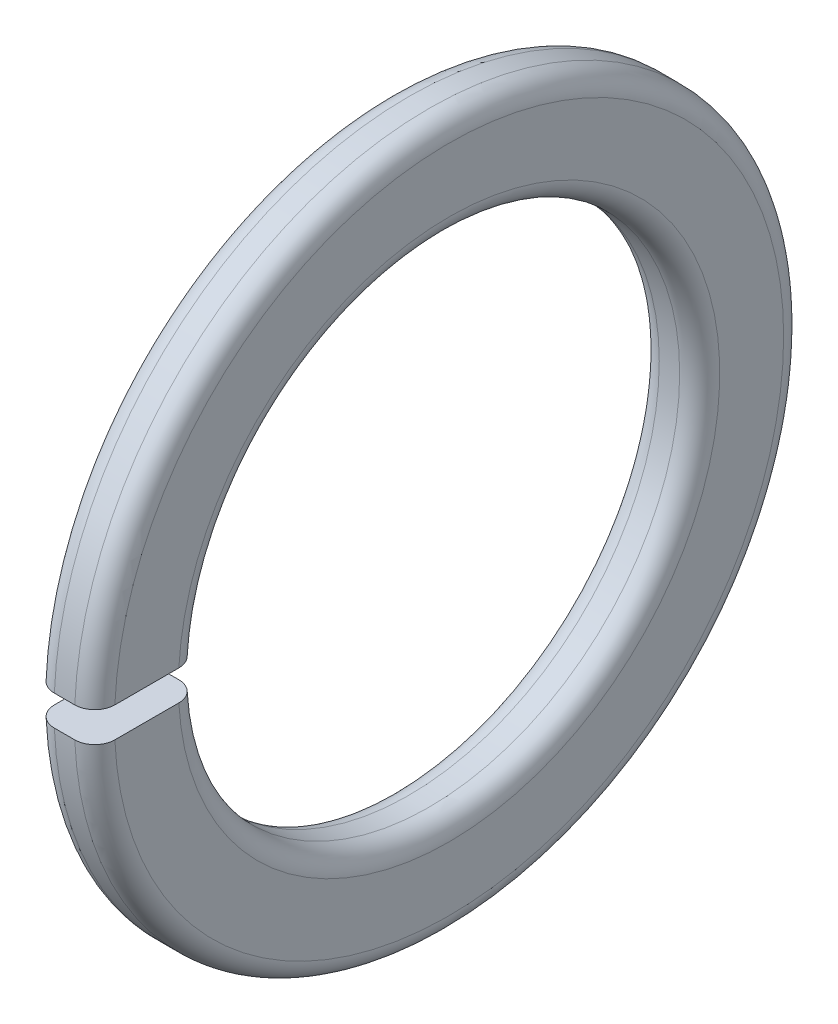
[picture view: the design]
ISO-10303-21;
HEADER;
FILE_DESCRIPTION(('STEP AP214'),'2;1');
FILE_NAME('part.step','',(''),(''),'','','');
FILE_SCHEMA(('AUTOMOTIVE_DESIGN { 1 0 10303 214 1 1 1 1 }'));
ENDSEC;
DATA;
#1=APPLICATION_CONTEXT('core data for automotive mechanical design processes');
#2=APPLICATION_PROTOCOL_DEFINITION('international standard','automotive_design',2000,#1);
#3=PRODUCT_CONTEXT('',#1,'mechanical');
#4=PRODUCT('Part','Part','',(#3));
#5=PRODUCT_RELATED_PRODUCT_CATEGORY('part','',(#4));
#6=PRODUCT_DEFINITION_FORMATION('','',#4);
#7=PRODUCT_DEFINITION_CONTEXT('part definition',#1,'design');
#8=PRODUCT_DEFINITION('design','',#6,#7);
#9=PRODUCT_DEFINITION_SHAPE('','',#8);
#10=(LENGTH_UNIT() NAMED_UNIT(*) SI_UNIT(.MILLI.,.METRE.));
#11=(NAMED_UNIT(*) PLANE_ANGLE_UNIT() SI_UNIT($,.RADIAN.));
#12=(NAMED_UNIT(*) SI_UNIT($,.STERADIAN.) SOLID_ANGLE_UNIT());
#13=UNCERTAINTY_MEASURE_WITH_UNIT(LENGTH_MEASURE(1.E-05),#10,'distance_accuracy_value','');
#14=(GEOMETRIC_REPRESENTATION_CONTEXT(3) GLOBAL_UNCERTAINTY_ASSIGNED_CONTEXT((#13)) GLOBAL_UNIT_ASSIGNED_CONTEXT((#10,
#11,#12)) REPRESENTATION_CONTEXT('',''));
#15=CARTESIAN_POINT('',(0.,0.,0.));
#16=DIRECTION('',(0.,0.,1.));
#17=DIRECTION('',(1.,0.,0.));
#18=AXIS2_PLACEMENT_3D('',#15,#16,#17);
#19=CARTESIAN_POINT('',(-5.35,0.,0.));
#20=DIRECTION('',(-1.,0.,0.));
#21=DIRECTION('',(0.,0.,1.));
#22=AXIS2_PLACEMENT_3D('',#19,#20,#21);
#23=TOROIDAL_SURFACE('',#22,35.8,2.65);
#24=CARTESIAN_POINT('',(-5.35,0.,0.));
#25=DIRECTION('',(-1.,0.,0.));
#26=DIRECTION('',(0.,0.,1.));
#27=AXIS2_PLACEMENT_3D('',#24,#25,#26);
#28=CIRCLE('',#27,33.15);
#29=CARTESIAN_POINT('',(-5.35,2.,33.0896131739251));
#30=VERTEX_POINT('',#29);
#31=CARTESIAN_POINT('',(-5.35,-2.,33.0896131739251));
#32=VERTEX_POINT('',#31);
#33=EDGE_CURVE('E129',#30,#32,#28,.T.);
#34=ORIENTED_EDGE('',*,*,#33,.F.);
#35=CARTESIAN_POINT('',(-6.71722156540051,2.,33.4702314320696));
#36=CARTESIAN_POINT('',(-6.84479830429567,2.,33.5472135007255));
#37=CARTESIAN_POINT('',(-6.96595921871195,2.,33.6350404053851));
#38=CARTESIAN_POINT('',(-7.19190739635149,2.,33.829873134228));
#39=CARTESIAN_POINT('',(-7.29667443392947,2.,33.9369023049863));
#40=CARTESIAN_POINT('',(-7.48670911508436,2.,34.1669771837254));
#41=CARTESIAN_POINT('',(-7.5719874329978,2.,34.2900140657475));
#42=CARTESIAN_POINT('',(-7.72068105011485,2.,34.5486108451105));
#43=CARTESIAN_POINT('',(-7.78410177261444,2.,34.6841676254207));
#44=CARTESIAN_POINT('',(-7.88739900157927,2.,34.9641700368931));
#45=CARTESIAN_POINT('',(-7.92724549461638,2.,35.1086267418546));
#46=CARTESIAN_POINT('',(-7.98214679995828,2.,35.4021828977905));
#47=CARTESIAN_POINT('',(-7.99720047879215,2.,35.5512825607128));
#48=CARTESIAN_POINT('',(-8.00208976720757,2.,35.8500277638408));
#49=CARTESIAN_POINT('',(-7.99190300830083,2.,35.9996736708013));
#50=CARTESIAN_POINT('',(-7.94654776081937,2.,36.2951307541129));
#51=CARTESIAN_POINT('',(-7.91137930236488,2.,36.4409419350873));
#52=CARTESIAN_POINT('',(-7.81705482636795,2.,36.7245672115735));
#53=CARTESIAN_POINT('',(-7.75790190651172,2.,36.8623823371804));
#54=CARTESIAN_POINT('',(-7.61727610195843,2.,37.126111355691));
#55=CARTESIAN_POINT('',(-7.53580335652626,2.,37.2520253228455));
#56=CARTESIAN_POINT('',(-7.35293406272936,2.,37.4882401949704));
#57=CARTESIAN_POINT('',(-7.25155754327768,2.,37.5985566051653));
#58=CARTESIAN_POINT('',(-7.03169977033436,2.,37.8005749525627));
#59=CARTESIAN_POINT('',(-6.91321862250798,2.,37.8922770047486));
#60=CARTESIAN_POINT('',(-6.66269124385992,2.,38.0543283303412));
#61=CARTESIAN_POINT('',(-6.53066406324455,2.,38.1247070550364));
#62=CARTESIAN_POINT('',(-6.25665775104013,2.,38.2422690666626));
#63=CARTESIAN_POINT('',(-6.11467869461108,2.,38.2894525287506));
#64=CARTESIAN_POINT('',(-5.82498400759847,2.,38.3592293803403));
#65=CARTESIAN_POINT('',(-5.67727553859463,2.,38.3818525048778));
#66=CARTESIAN_POINT('',(-5.38015750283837,2.,38.4019630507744));
#67=CARTESIAN_POINT('',(-5.23074794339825,2.,38.3994505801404));
#68=CARTESIAN_POINT('',(-4.9345633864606,2.,38.3693711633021));
#69=CARTESIAN_POINT('',(-4.78778686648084,2.,38.3418192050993));
#70=CARTESIAN_POINT('',(-4.50094127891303,2.,38.2624697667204));
#71=CARTESIAN_POINT('',(-4.36087220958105,2.,38.2106722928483));
#72=CARTESIAN_POINT('',(-4.09138125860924,2.,38.0842971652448));
#73=CARTESIAN_POINT('',(-3.96196171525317,2.,38.0097145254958));
#74=CARTESIAN_POINT('',(-3.71746522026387,2.,37.8398998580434));
#75=CARTESIAN_POINT('',(-3.6023883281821,2.,37.7446677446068));
#76=CARTESIAN_POINT('',(-3.3897221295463,2.,37.5361629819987));
#77=CARTESIAN_POINT('',(-3.29214974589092,2.,37.4228730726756));
#78=CARTESIAN_POINT('',(-3.1173786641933,2.,37.1815393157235));
#79=CARTESIAN_POINT('',(-3.04018010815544,2.,37.0534953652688));
#80=CARTESIAN_POINT('',(-2.90823555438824,2.,36.7861009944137));
#81=CARTESIAN_POINT('',(-2.85352042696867,2.,36.6467353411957));
#82=CARTESIAN_POINT('',(-2.76823109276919,2.,36.360803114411));
#83=CARTESIAN_POINT('',(-2.73765707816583,2.,36.2142364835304));
#84=CARTESIAN_POINT('',(-2.70148291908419,2.,35.9178656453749));
#85=CARTESIAN_POINT('',(-2.69591421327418,2.,35.7680576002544));
#86=CARTESIAN_POINT('',(-2.70999002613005,2.,35.4696305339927));
#87=CARTESIAN_POINT('',(-2.72963464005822,2.,35.321011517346));
#88=CARTESIAN_POINT('',(-2.79360178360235,2.,35.0290891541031));
#89=CARTESIAN_POINT('',(-2.83793900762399,2.,34.8857890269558));
#90=CARTESIAN_POINT('',(-2.95005178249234,2.,34.608670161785));
#91=CARTESIAN_POINT('',(-3.01782736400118,2.,34.4748514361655));
#92=CARTESIAN_POINT('',(-3.17487121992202,2.,34.2205596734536));
#93=CARTESIAN_POINT('',(-3.26413052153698,2.,34.1000810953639));
#94=CARTESIAN_POINT('',(-3.46163418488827,2.,33.8758444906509));
#95=CARTESIAN_POINT('',(-3.56987846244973,2.,33.7720863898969));
#96=CARTESIAN_POINT('',(-3.80212822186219,2.,33.5843882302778));
#97=CARTESIAN_POINT('',(-3.9261125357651,2.,33.500421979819));
#98=CARTESIAN_POINT('',(-4.18643262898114,2.,33.3545415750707));
#99=CARTESIAN_POINT('',(-4.32276780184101,2.,33.2926263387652));
#100=CARTESIAN_POINT('',(-4.60365809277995,2.,33.1927146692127));
#101=CARTESIAN_POINT('',(-4.74819788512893,2.,33.1546751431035));
#102=CARTESIAN_POINT('',(-5.04165499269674,2.,33.1034274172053));
#103=CARTESIAN_POINT('',(-5.19057335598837,2.,33.0902252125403));
#104=CARTESIAN_POINT('',(-5.4883866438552,2.,33.0890429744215));
#105=CARTESIAN_POINT('',(-5.63728150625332,2.,33.101044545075));
#106=CARTESIAN_POINT('',(-5.93081204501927,2.,33.1498886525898));
#107=CARTESIAN_POINT('',(-6.07545265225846,2.,33.1867011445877));
#108=CARTESIAN_POINT('',(-6.30326333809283,2.,33.2655921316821));
#109=CARTESIAN_POINT('',(-6.38901271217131,2.,33.300427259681));
#110=CARTESIAN_POINT('',(-6.55640555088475,2.,33.3788598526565));
#111=CARTESIAN_POINT('',(-6.63804901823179,2.,33.4224573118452));
#112=CARTESIAN_POINT('',(-6.71722156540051,2.,33.4702314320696));
#113=B_SPLINE_CURVE_WITH_KNOTS('',3,(#35,#36,#37,#38,#39,#40,#41,#42,#43,#44,#45,#46,#47,#48,
#49,#50,#51,#52,#53,#54,#55,#56,#57,#58,#59,#60,#61,#62,#63,#64,#65,#66,#67,#68,#69,#70,#71,#72,
#73,#74,#75,#76,#77,#78,#79,#80,#81,#82,#83,#84,#85,#86,#87,#88,#89,#90,#91,#92,#93,#94,#95,#96,
#97,#98,#99,#100,#101,#102,#103,#104,#105,#106,#107,#108,#109,#110,#111,#112),.UNSPECIFIED.,.T.,
.F.,(4,2,2,2,2,2,2,2,2,2,2,2,2,2,2,2,2,2,2,2,2,2,2,2,2,2,2,2,2,2,2,2,2,2,2,2,2,2,4),(0.,
0.446672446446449,0.893891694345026,1.34086540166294,1.78772812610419,2.23515855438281,
2.68260943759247,3.13045700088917,3.57830402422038,4.02609322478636,4.47387963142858,
4.92121772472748,5.36855305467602,5.81526768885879,6.26197894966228,6.70814877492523,
7.15431668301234,7.60021770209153,8.04611860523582,8.49211715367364,8.93811755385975,
9.384546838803,9.83097923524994,10.2780225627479,10.7250694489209,11.1726782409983,
11.6202887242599,12.0681658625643,12.5160435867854,12.963734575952,13.4114235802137,
13.8585167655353,14.305588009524,14.7518500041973,15.1982197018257,15.6442637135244,
16.0897685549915,16.3669681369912,16.6441675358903),.UNSPECIFIED.);
#114=CARTESIAN_POINT('',(-8.,2.,35.7440904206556));
#115=VERTEX_POINT('',#114);
#116=EDGE_CURVE('E53',#30,#115,#113,.T.);
#117=ORIENTED_EDGE('',*,*,#116,.T.);
#118=CARTESIAN_POINT('',(-8.,0.,0.));
#119=DIRECTION('',(-1.,0.,0.));
#120=DIRECTION('',(0.,0.,1.));
#121=AXIS2_PLACEMENT_3D('',#118,#119,#120);
#122=CIRCLE('',#121,35.8);
#123=CARTESIAN_POINT('',(-8.,-2.,35.7440904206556));
#124=VERTEX_POINT('',#123);
#125=EDGE_CURVE('E141',#115,#124,#122,.T.);
#126=ORIENTED_EDGE('',*,*,#125,.T.);
#127=CARTESIAN_POINT('',(-6.71722156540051,-2.,33.4702314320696));
#128=CARTESIAN_POINT('',(-6.58992742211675,-2.,33.3934353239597));
#129=CARTESIAN_POINT('',(-6.45606218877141,-2.,33.3273234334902));
#130=CARTESIAN_POINT('',(-6.17902217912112,-2.,33.2184562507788));
#131=CARTESIAN_POINT('',(-6.03583656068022,-2.,33.1757287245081));
#132=CARTESIAN_POINT('',(-5.74437135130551,-2.,33.1149479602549));
#133=CARTESIAN_POINT('',(-5.59609400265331,-2.,33.0968840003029));
#134=CARTESIAN_POINT('',(-5.29865213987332,-2.,33.0859280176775));
#135=CARTESIAN_POINT('',(-5.14948785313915,-2.,33.0930297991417));
#136=CARTESIAN_POINT('',(-4.85453503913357,-2.,33.1321755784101));
#137=CARTESIAN_POINT('',(-4.70874506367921,-2.,33.164208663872));
#138=CARTESIAN_POINT('',(-4.42460331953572,-2.,33.2522870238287));
#139=CARTESIAN_POINT('',(-4.28625184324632,-2.,33.3083332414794));
#140=CARTESIAN_POINT('',(-4.02085091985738,-2.,33.4428624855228));
#141=CARTESIAN_POINT('',(-3.89380636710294,-2.,33.5213551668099));
#142=CARTESIAN_POINT('',(-3.65467368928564,-2.,33.6985262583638));
#143=CARTESIAN_POINT('',(-3.54258563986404,-2.,33.7972047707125));
#144=CARTESIAN_POINT('',(-3.33637138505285,-2.,34.0120965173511));
#145=CARTESIAN_POINT('',(-3.24227141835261,-2.,34.1283349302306));
#146=CARTESIAN_POINT('',(-3.07488285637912,-2.,34.374937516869));
#147=CARTESIAN_POINT('',(-3.00159441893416,-2.,34.5053017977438));
#148=CARTESIAN_POINT('',(-2.87778215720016,-2.,34.7766916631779));
#149=CARTESIAN_POINT('',(-2.8272968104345,-2.,34.9177348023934));
#150=CARTESIAN_POINT('',(-2.75069197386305,-2.,35.2062900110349));
#151=CARTESIAN_POINT('',(-2.7245726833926,-2.,35.3538021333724));
#152=CARTESIAN_POINT('',(-2.69742089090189,-2.,35.6512829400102));
#153=CARTESIAN_POINT('',(-2.69641622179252,-2.,35.8012541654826));
#154=CARTESIAN_POINT('',(-2.71959596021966,-2.,36.0992375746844));
#155=CARTESIAN_POINT('',(-2.7437804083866,-2.,36.2472497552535));
#156=CARTESIAN_POINT('',(-2.81666433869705,-2.,36.5371264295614));
#157=CARTESIAN_POINT('',(-2.86536626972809,-2.,36.6789903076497));
#158=CARTESIAN_POINT('',(-2.98591548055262,-2.,36.9525180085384));
#159=CARTESIAN_POINT('',(-3.05776268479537,-2.,37.0841818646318));
#160=CARTESIAN_POINT('',(-3.22250313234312,-2.,37.3334497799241));
#161=CARTESIAN_POINT('',(-3.31537857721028,-2.,37.4510656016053));
#162=CARTESIAN_POINT('',(-3.51958167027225,-2.,37.6690088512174));
#163=CARTESIAN_POINT('',(-3.63090919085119,-2.,37.7693363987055));
#164=CARTESIAN_POINT('',(-3.86869555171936,-2.,37.9497101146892));
#165=CARTESIAN_POINT('',(-3.99513374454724,-2.,38.0297835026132));
#166=CARTESIAN_POINT('',(-4.25967225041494,-2.,38.1675344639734));
#167=CARTESIAN_POINT('',(-4.39777247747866,-2.,38.2252122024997));
#168=CARTESIAN_POINT('',(-4.68152226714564,-2.,38.3164595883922));
#169=CARTESIAN_POINT('',(-4.8271618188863,-2.,38.3500603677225));
#170=CARTESIAN_POINT('',(-5.12201587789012,-2.,38.3923134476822));
#171=CARTESIAN_POINT('',(-5.27123036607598,-2.,38.4009658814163));
#172=CARTESIAN_POINT('',(-5.56887772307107,-2.,38.3930777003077));
#173=CARTESIAN_POINT('',(-5.71731110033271,-2.,38.3765562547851));
#174=CARTESIAN_POINT('',(-6.00929711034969,-2.,38.3188284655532));
#175=CARTESIAN_POINT('',(-6.15284974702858,-2.,38.2776221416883));
#176=CARTESIAN_POINT('',(-6.43100776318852,-2.,38.1717004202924));
#177=CARTESIAN_POINT('',(-6.56561282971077,-2.,38.106984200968));
#178=CARTESIAN_POINT('',(-6.82205928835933,-2.,37.9558897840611));
#179=CARTESIAN_POINT('',(-6.94390065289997,-2.,37.8695115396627));
#180=CARTESIAN_POINT('',(-7.17147138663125,-2.,37.6774738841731));
#181=CARTESIAN_POINT('',(-7.27718750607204,-2.,37.5717987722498));
#182=CARTESIAN_POINT('',(-7.46940639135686,-2.,37.3442205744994));
#183=CARTESIAN_POINT('',(-7.5559089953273,-2.,37.2223173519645));
#184=CARTESIAN_POINT('',(-7.70736756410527,-2.,36.9655725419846));
#185=CARTESIAN_POINT('',(-7.77229500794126,-2.,36.8307141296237));
#186=CARTESIAN_POINT('',(-7.87862198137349,-2.,36.5520207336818));
#187=CARTESIAN_POINT('',(-7.92002128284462,-2.,36.4081856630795));
#188=CARTESIAN_POINT('',(-7.97817124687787,-2.,36.1154143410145));
#189=CARTESIAN_POINT('',(-7.99488857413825,-2.,35.9664714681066));
#190=CARTESIAN_POINT('',(-8.00310119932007,-2.,35.6678973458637));
#191=CARTESIAN_POINT('',(-7.99459733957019,-2.,35.5182661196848));
#192=CARTESIAN_POINT('',(-7.95259793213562,-2.,35.2224497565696));
#193=CARTESIAN_POINT('',(-7.91908542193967,-2.,35.0762670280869));
#194=CARTESIAN_POINT('',(-7.8279783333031,-2.,34.7915647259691));
#195=CARTESIAN_POINT('',(-7.77037776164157,-2.,34.6530470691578));
#196=CARTESIAN_POINT('',(-7.63271363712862,-2.,34.3876273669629));
#197=CARTESIAN_POINT('',(-7.55264340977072,-2.,34.2607287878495));
#198=CARTESIAN_POINT('',(-7.37236153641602,-2.,34.0223163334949));
#199=CARTESIAN_POINT('',(-7.27217432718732,-2.,33.9107840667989));
#200=CARTESIAN_POINT('',(-7.09527305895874,-2.,33.7444674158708));
#201=CARTESIAN_POINT('',(-7.02376787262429,-2.,33.6840465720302));
#202=CARTESIAN_POINT('',(-6.87478251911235,-2.,33.5710848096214));
#203=CARTESIAN_POINT('',(-6.79730235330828,-2.,33.5185438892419));
#204=CARTESIAN_POINT('',(-6.71722156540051,-2.,33.4702314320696));
#205=B_SPLINE_CURVE_WITH_KNOTS('',3,(#127,#128,#129,#130,#131,#132,#133,#134,#135,#136,#137,
#138,#139,#140,#141,#142,#143,#144,#145,#146,#147,#148,#149,#150,#151,#152,#153,#154,#155,#156,
#157,#158,#159,#160,#161,#162,#163,#164,#165,#166,#167,#168,#169,#170,#171,#172,#173,#174,#175,
#176,#177,#178,#179,#180,#181,#182,#183,#184,#185,#186,#187,#188,#189,#190,#191,#192,#193,#194,
#195,#196,#197,#198,#199,#200,#201,#202,#203,#204),.UNSPECIFIED.,.T.,.F.,(4,2,2,2,2,2,2,2,2,2,2,
2,2,2,2,2,2,2,2,2,2,2,2,2,2,2,2,2,2,2,2,2,2,2,2,2,2,2,4),(0.,0.445655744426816,
0.891839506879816,1.3378292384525,1.78370917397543,2.22939405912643,2.67509645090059,
3.12099084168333,3.5668874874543,4.01342966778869,4.45997523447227,4.9072715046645,
5.35457143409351,5.80236705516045,6.25016339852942,6.69800447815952,7.14584409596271,
7.59330606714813,8.04076494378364,8.48761924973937,8.93447026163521,9.38074243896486,
9.82701223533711,10.2729423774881,10.7188721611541,11.164817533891,11.610763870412,
12.057074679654,12.5033892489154,12.9502914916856,13.3971980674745,13.8447076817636,
14.2922023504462,14.7400008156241,15.1879107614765,15.6359538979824,16.0834560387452,
16.3638182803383,16.6441804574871),.UNSPECIFIED.);
#206=EDGE_CURVE('E120',#124,#32,#205,.T.);
#207=ORIENTED_EDGE('',*,*,#206,.T.);
#208=EDGE_LOOP('',(#34,#117,#126,#207));
#209=FACE_BOUND('',#208,.T.);
#210=ADVANCED_FACE('F39',(#209),#23,.T.);
#211=CARTESIAN_POINT('',(-8.,44.25,0.));
#212=DIRECTION('',(1.,0.,0.));
#213=DIRECTION('',(0.,0.,-1.));
#214=AXIS2_PLACEMENT_3D('',#211,#212,#213);
#215=PLANE('',#214);
#216=DIRECTION('',(0.,0.,-1.));
#217=VECTOR('',#216,1.);
#218=CARTESIAN_POINT('',(-8.,2.,47.838));
#219=LINE('',#218,#217);
#220=CARTESIAN_POINT('',(-8.,2.,44.2047791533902));
#221=VERTEX_POINT('',#220);
#222=EDGE_CURVE('E109',#221,#115,#219,.T.);
#223=ORIENTED_EDGE('',*,*,#222,.F.);
#224=CARTESIAN_POINT('',(-8.,0.,0.));
#225=DIRECTION('',(-1.,0.,0.));
#226=DIRECTION('',(0.,0.,1.));
#227=AXIS2_PLACEMENT_3D('',#224,#225,#226);
#228=CIRCLE('',#227,44.25);
#229=CARTESIAN_POINT('',(-8.,-2.,44.2047791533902));
#230=VERTEX_POINT('',#229);
#231=EDGE_CURVE('E138',#221,#230,#228,.T.);
#232=ORIENTED_EDGE('',*,*,#231,.T.);
#233=DIRECTION('',(0.,0.,1.));
#234=VECTOR('',#233,1.);
#235=CARTESIAN_POINT('',(-8.,-2.,0.));
#236=LINE('',#235,#234);
#237=EDGE_CURVE('E121',#124,#230,#236,.T.);
#238=ORIENTED_EDGE('',*,*,#237,.F.);
#239=ORIENTED_EDGE('',*,*,#125,.F.);
#240=EDGE_LOOP('',(#223,#232,#238,#239));
#241=FACE_BOUND('',#240,.T.);
#242=ADVANCED_FACE('F214',(#241),#215,.F.);
#243=CARTESIAN_POINT('',(-5.35,0.,0.));
#244=DIRECTION('',(-1.,0.,0.));
#245=DIRECTION('',(0.,0.,1.));
#246=AXIS2_PLACEMENT_3D('',#243,#244,#245);
#247=TOROIDAL_SURFACE('',#246,44.25,2.65);
#248=CARTESIAN_POINT('',(-7.15266997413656,2.,42.2603102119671));
#249=CARTESIAN_POINT('',(-7.04365111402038,2.,42.1590290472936));
#250=CARTESIAN_POINT('',(-6.92600703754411,2.,42.0668738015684));
#251=CARTESIAN_POINT('',(-6.67682053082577,2.,41.9035436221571));
#252=CARTESIAN_POINT('',(-6.54526171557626,2.,41.8323938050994));
#253=CARTESIAN_POINT('',(-6.27210721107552,2.,41.7132272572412));
#254=CARTESIAN_POINT('',(-6.13051592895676,2.,41.6652004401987));
#255=CARTESIAN_POINT('',(-5.84131537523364,2.,41.5936310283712));
#256=CARTESIAN_POINT('',(-5.69370760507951,2.,41.5700823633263));
#257=CARTESIAN_POINT('',(-5.39670920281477,2.,41.5481241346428));
#258=CARTESIAN_POINT('',(-5.24731952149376,2.,41.5497017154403));
#259=CARTESIAN_POINT('',(-4.95092118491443,2.,41.5779209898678));
#260=CARTESIAN_POINT('',(-4.80391261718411,2.,41.6045636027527));
#261=CARTESIAN_POINT('',(-4.51648771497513,2.,41.6821433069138));
#262=CARTESIAN_POINT('',(-4.37606992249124,2.,41.7330749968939));
#263=CARTESIAN_POINT('',(-4.10577142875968,2.,41.8577765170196));
#264=CARTESIAN_POINT('',(-3.97589072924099,2.,41.9315463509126));
#265=CARTESIAN_POINT('',(-3.73027060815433,2.,42.0998704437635));
#266=CARTESIAN_POINT('',(-3.61453928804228,2.,42.1944365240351));
#267=CARTESIAN_POINT('',(-3.40057506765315,2.,42.4016374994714));
#268=CARTESIAN_POINT('',(-3.30234223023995,2.,42.5142724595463));
#269=CARTESIAN_POINT('',(-3.12605353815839,2.,42.7545392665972));
#270=CARTESIAN_POINT('',(-3.04801883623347,2.,42.8821866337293));
#271=CARTESIAN_POINT('',(-2.91446215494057,2.,43.1487606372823));
#272=CARTESIAN_POINT('',(-2.85894032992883,2.,43.2876873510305));
#273=CARTESIAN_POINT('',(-2.77193099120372,2.,43.5730254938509));
#274=CARTESIAN_POINT('',(-2.74046751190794,2.,43.7194442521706));
#275=CARTESIAN_POINT('',(-2.70255493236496,2.,44.0154853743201));
#276=CARTESIAN_POINT('',(-2.69610591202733,2.,44.1651077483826));
#277=CARTESIAN_POINT('',(-2.70840885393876,2.,44.4633884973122));
#278=CARTESIAN_POINT('',(-2.72717346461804,2.,44.612046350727));
#279=CARTESIAN_POINT('',(-2.78939797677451,2.,44.9041008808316));
#280=CARTESIAN_POINT('',(-2.83285788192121,2.,45.0474975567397));
#281=CARTESIAN_POINT('',(-2.94323686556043,2.,45.3249303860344));
#282=CARTESIAN_POINT('',(-3.01015191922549,2.,45.4589681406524));
#283=CARTESIAN_POINT('',(-3.1655507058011,2.,45.7138961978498));
#284=CARTESIAN_POINT('',(-3.2540343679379,2.,45.8347865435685));
#285=CARTESIAN_POINT('',(-3.44999306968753,2.,46.0598939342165));
#286=CARTESIAN_POINT('',(-3.55745450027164,2.,46.1641228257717));
#287=CARTESIAN_POINT('',(-3.78836482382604,2.,46.3530396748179));
#288=CARTESIAN_POINT('',(-3.91181363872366,2.,46.4377277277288));
#289=CARTESIAN_POINT('',(-4.17107163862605,2.,46.5850761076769));
#290=CARTESIAN_POINT('',(-4.3068692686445,2.,46.6477567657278));
#291=CARTESIAN_POINT('',(-4.58706562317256,2.,46.7494100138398));
#292=CARTESIAN_POINT('',(-4.7314643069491,2.,46.7883827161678));
#293=CARTESIAN_POINT('',(-5.02464523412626,2.,46.8414862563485));
#294=CARTESIAN_POINT('',(-5.17342404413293,2.,46.8556360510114));
#295=CARTESIAN_POINT('',(-5.47124473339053,2.,46.8587481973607));
#296=CARTESIAN_POINT('',(-5.62028661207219,2.,46.8477106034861));
#297=CARTESIAN_POINT('',(-5.91435322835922,2.,46.800770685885));
#298=CARTESIAN_POINT('',(-6.05937922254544,2.,46.7648762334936));
#299=CARTESIAN_POINT('',(-6.34134861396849,2.,46.6692547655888));
#300=CARTESIAN_POINT('',(-6.47829201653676,2.,46.609527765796));
#301=CARTESIAN_POINT('',(-6.7402470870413,2.,46.4679256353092));
#302=CARTESIAN_POINT('',(-6.86525585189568,2.,46.3860451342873));
#303=CARTESIAN_POINT('',(-7.09976531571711,2.,46.2024729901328));
#304=CARTESIAN_POINT('',(-7.20926593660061,2.,46.1007812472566));
#305=CARTESIAN_POINT('',(-7.40973601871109,2.,45.8803975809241));
#306=CARTESIAN_POINT('',(-7.50069219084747,2.,45.7616935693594));
#307=CARTESIAN_POINT('',(-7.66140673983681,2.,45.5107115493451));
#308=CARTESIAN_POINT('',(-7.7311649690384,2.,45.3784334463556));
#309=CARTESIAN_POINT('',(-7.84757221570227,2.,45.1039248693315));
#310=CARTESIAN_POINT('',(-7.89419936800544,2.,44.9616851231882));
#311=CARTESIAN_POINT('',(-7.96293032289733,2.,44.6714049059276));
#312=CARTESIAN_POINT('',(-7.98503496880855,2.,44.52336463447));
#313=CARTESIAN_POINT('',(-8.00410997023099,2.,44.2255757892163));
#314=CARTESIAN_POINT('',(-8.0010636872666,2.,44.0758261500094));
#315=CARTESIAN_POINT('',(-7.96987721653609,2.,43.7789215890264));
#316=CARTESIAN_POINT('',(-7.94173073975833,2.,43.6317673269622));
#317=CARTESIAN_POINT('',(-7.86111339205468,2.,43.3441768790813));
#318=CARTESIAN_POINT('',(-7.80862456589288,2.,43.2037457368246));
#319=CARTESIAN_POINT('',(-7.68083058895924,2.,42.9338218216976));
#320=CARTESIAN_POINT('',(-7.60555295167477,2.,42.8043160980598));
#321=CARTESIAN_POINT('',(-7.46642820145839,2.,42.6055953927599));
#322=CARTESIAN_POINT('',(-7.40881905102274,2.,42.5319329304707));
#323=CARTESIAN_POINT('',(-7.28616323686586,2.,42.3910846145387));
#324=CARTESIAN_POINT('',(-7.22111657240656,2.,42.3238987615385));
#325=CARTESIAN_POINT('',(-7.15266997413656,2.,42.2603102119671));
#326=B_SPLINE_CURVE_WITH_KNOTS('',3,(#248,#249,#250,#251,#252,#253,#254,#255,#256,#257,#258,
#259,#260,#261,#262,#263,#264,#265,#266,#267,#268,#269,#270,#271,#272,#273,#274,#275,#276,#277,
#278,#279,#280,#281,#282,#283,#284,#285,#286,#287,#288,#289,#290,#291,#292,#293,#294,#295,#296,
#297,#298,#299,#300,#301,#302,#303,#304,#305,#306,#307,#308,#309,#310,#311,#312,#313,#314,#315,
#316,#317,#318,#319,#320,#321,#322,#323,#324,#325),.UNSPECIFIED.,.T.,.F.,(4,2,2,2,2,2,2,2,2,2,2,
2,2,2,2,2,2,2,2,2,2,2,2,2,2,2,2,2,2,2,2,2,2,2,2,2,2,2,4),(0.,0.446075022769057,
0.892681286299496,1.33909256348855,1.78539311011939,2.23146531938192,2.67755388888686,
3.1235433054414,3.56953279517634,4.01577645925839,4.46202172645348,4.90873245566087,
5.35544624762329,5.80260572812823,6.24976663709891,6.6971519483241,7.14453732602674,
7.59184597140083,8.03915314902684,8.48614085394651,8.9331263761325,9.37969786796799,
9.82626724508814,10.2724954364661,10.7187226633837,11.1648086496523,11.6108943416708,
12.057088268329,12.5032844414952,12.9497992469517,13.3963171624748,13.8432563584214,
14.290180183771,14.7373996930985,15.1847312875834,15.6323933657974,16.0795171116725,
16.3595816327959,16.6396461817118),.UNSPECIFIED.);
#327=CARTESIAN_POINT('',(-5.35,2.,46.857336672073));
#328=VERTEX_POINT('',#327);
#329=EDGE_CURVE('E152',#328,#221,#326,.T.);
#330=ORIENTED_EDGE('',*,*,#329,.F.);
#331=CARTESIAN_POINT('',(-5.35,0.,0.));
#332=DIRECTION('',(-1.,0.,0.));
#333=DIRECTION('',(0.,0.,1.));
#334=AXIS2_PLACEMENT_3D('',#331,#332,#333);
#335=CIRCLE('',#334,46.9);
#336=CARTESIAN_POINT('',(-5.35,-2.,46.857336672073));
#337=VERTEX_POINT('',#336);
#338=EDGE_CURVE('E135',#328,#337,#335,.T.);
#339=ORIENTED_EDGE('',*,*,#338,.T.);
#340=CARTESIAN_POINT('',(-7.15266997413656,-2.,42.2603102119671));
#341=CARTESIAN_POINT('',(-7.26185054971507,-2.,42.3617596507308));
#342=CARTESIAN_POINT('',(-7.3625372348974,-2.,42.4725109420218));
#343=CARTESIAN_POINT('',(-7.54396461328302,-2.,42.7094432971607));
#344=CARTESIAN_POINT('',(-7.62468086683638,-2.,42.8356429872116));
#345=CARTESIAN_POINT('',(-7.76374733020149,-2.,43.0997476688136));
#346=CARTESIAN_POINT('',(-7.82210906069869,-2.,43.2376465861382));
#347=CARTESIAN_POINT('',(-7.91485093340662,-2.,43.5212434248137));
#348=CARTESIAN_POINT('',(-7.94923705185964,-2.,43.6669393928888));
#349=CARTESIAN_POINT('',(-7.99310062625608,-2.,43.9621375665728));
#350=CARTESIAN_POINT('',(-8.00256090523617,-2.,44.1116423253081));
#351=CARTESIAN_POINT('',(-7.99625357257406,-2.,44.4101247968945));
#352=CARTESIAN_POINT('',(-7.98048490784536,-2.,44.5591024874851));
#353=CARTESIAN_POINT('',(-7.92415596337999,-2.,44.852324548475));
#354=CARTESIAN_POINT('',(-7.88359100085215,-2.,44.9965680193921));
#355=CARTESIAN_POINT('',(-7.77880997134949,-2.,45.2761924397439));
#356=CARTESIAN_POINT('',(-7.71459398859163,-2.,45.4115734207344));
#357=CARTESIAN_POINT('',(-7.56435994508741,-2.,45.669563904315));
#358=CARTESIAN_POINT('',(-7.47835148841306,-2.,45.7921789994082));
#359=CARTESIAN_POINT('',(-7.2869538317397,-2.,46.0212132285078));
#360=CARTESIAN_POINT('',(-7.18156474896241,-2.,46.127632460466));
#361=CARTESIAN_POINT('',(-6.95449298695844,-2.,46.3211564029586));
#362=CARTESIAN_POINT('',(-6.83282430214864,-2.,46.4082775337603));
#363=CARTESIAN_POINT('',(-6.57657667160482,-2.,46.5608352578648));
#364=CARTESIAN_POINT('',(-6.44199777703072,-2.,46.626271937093));
#365=CARTESIAN_POINT('',(-6.16388024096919,-2.,46.7335428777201));
#366=CARTESIAN_POINT('',(-6.02034975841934,-2.,46.7753982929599));
#367=CARTESIAN_POINT('',(-5.7282973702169,-2.,46.8344022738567));
#368=CARTESIAN_POINT('',(-5.5797754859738,-2.,46.8515509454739));
#369=CARTESIAN_POINT('',(-5.28205041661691,-2.,46.8606490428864));
#370=CARTESIAN_POINT('',(-5.13284768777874,-2.,46.8526134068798));
#371=CARTESIAN_POINT('',(-4.83790975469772,-2.,46.8116049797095));
#372=CARTESIAN_POINT('',(-4.69217454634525,-2.,46.7786322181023));
#373=CARTESIAN_POINT('',(-4.40831802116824,-2.,46.6886935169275));
#374=CARTESIAN_POINT('',(-4.27019615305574,-2.,46.6317293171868));
#375=CARTESIAN_POINT('',(-4.00547008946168,-2.,46.4954313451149));
#376=CARTESIAN_POINT('',(-3.87886591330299,-2.,46.4160975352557));
#377=CARTESIAN_POINT('',(-3.64070242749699,-2.,46.2372755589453));
#378=CARTESIAN_POINT('',(-3.52915027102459,-2.,46.1377778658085));
#379=CARTESIAN_POINT('',(-3.32431611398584,-2.,45.9214809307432));
#380=CARTESIAN_POINT('',(-3.23103419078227,-2.,45.804681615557));
#381=CARTESIAN_POINT('',(-3.0653029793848,-2.,45.5569916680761));
#382=CARTESIAN_POINT('',(-2.99287144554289,-2.,45.4260891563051));
#383=CARTESIAN_POINT('',(-2.87099029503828,-2.,45.1539899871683));
#384=CARTESIAN_POINT('',(-2.821540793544,-2.,45.01279327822));
#385=CARTESIAN_POINT('',(-2.74698249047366,-2.,44.7239771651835));
#386=CARTESIAN_POINT('',(-2.72189569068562,-2.,44.5763520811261));
#387=CARTESIAN_POINT('',(-2.69684641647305,-2.,44.2789853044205));
#388=CARTESIAN_POINT('',(-2.69688405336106,-2.,44.1292436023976));
#389=CARTESIAN_POINT('',(-2.72208861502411,-2.,43.8318023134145));
#390=CARTESIAN_POINT('',(-2.7472701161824,-2.,43.6841039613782));
#391=CARTESIAN_POINT('',(-2.822072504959,-2.,43.3950311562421));
#392=CARTESIAN_POINT('',(-2.87169339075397,-2.,43.2536567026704));
#393=CARTESIAN_POINT('',(-2.99397062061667,-2.,42.9812523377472));
#394=CARTESIAN_POINT('',(-3.06662627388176,-2.,42.8502221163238));
#395=CARTESIAN_POINT('',(-3.23291883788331,-2.,42.6022299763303));
#396=CARTESIAN_POINT('',(-3.32655572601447,-2.,42.4852680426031));
#397=CARTESIAN_POINT('',(-3.53208714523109,-2.,42.268822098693));
#398=CARTESIAN_POINT('',(-3.64396909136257,-2.,42.1693261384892));
#399=CARTESIAN_POINT('',(-3.88286450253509,-2.,41.9905537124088));
#400=CARTESIAN_POINT('',(-4.00987791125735,-2.,41.9112771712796));
#401=CARTESIAN_POINT('',(-4.27528772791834,-2.,41.7752831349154));
#402=CARTESIAN_POINT('',(-4.41367204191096,-2.,41.7185420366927));
#403=CARTESIAN_POINT('',(-4.69800284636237,-2.,41.6291254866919));
#404=CARTESIAN_POINT('',(-4.8439489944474,-2.,41.5964489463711));
#405=CARTESIAN_POINT('',(-5.13910040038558,-2.,41.5561141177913));
#406=CARTESIAN_POINT('',(-5.28830206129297,-2.,41.5484294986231));
#407=CARTESIAN_POINT('',(-5.58591709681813,-2.,41.5582285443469));
#408=CARTESIAN_POINT('',(-5.73433026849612,-2.,41.5757184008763));
#409=CARTESIAN_POINT('',(-6.02611805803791,-2.,41.6353693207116));
#410=CARTESIAN_POINT('',(-6.16949201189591,-2.,41.6775336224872));
#411=CARTESIAN_POINT('',(-6.44700144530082,-2.,41.7853088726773));
#412=CARTESIAN_POINT('',(-6.58114783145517,-2.,41.8508915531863));
#413=CARTESIAN_POINT('',(-6.78832693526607,-2.,41.9747516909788));
#414=CARTESIAN_POINT('',(-6.86535173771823,-2.,42.0264813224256));
#415=CARTESIAN_POINT('',(-7.01356963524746,-2.,42.1377112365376));
#416=CARTESIAN_POINT('',(-7.08476273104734,-2.,42.1972115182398));
#417=CARTESIAN_POINT('',(-7.15266997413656,-2.,42.2603102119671));
#418=B_SPLINE_CURVE_WITH_KNOTS('',3,(#340,#341,#342,#343,#344,#345,#346,#347,#348,#349,#350,
#351,#352,#353,#354,#355,#356,#357,#358,#359,#360,#361,#362,#363,#364,#365,#366,#367,#368,#369,
#370,#371,#372,#373,#374,#375,#376,#377,#378,#379,#380,#381,#382,#383,#384,#385,#386,#387,#388,
#389,#390,#391,#392,#393,#394,#395,#396,#397,#398,#399,#400,#401,#402,#403,#404,#405,#406,#407,
#408,#409,#410,#411,#412,#413,#414,#415,#416,#417),.UNSPECIFIED.,.T.,.F.,(4,2,2,2,2,2,2,2,2,2,2,
2,2,2,2,2,2,2,2,2,2,2,2,2,2,2,2,2,2,2,2,2,2,2,2,2,2,2,4),(0.,0.446775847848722,
0.894095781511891,1.3411848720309,1.78816247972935,2.23544802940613,2.68275224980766,
3.1301409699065,3.57752809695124,4.02471839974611,4.47190599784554,4.91871162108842,
5.3655154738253,5.81191787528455,6.25831836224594,6.70445411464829,7.15058933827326,
7.59669221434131,8.04279583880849,8.48911072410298,8.93542749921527,9.3821232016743,
9.82882114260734,10.2759221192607,10.7230250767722,11.1703873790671,11.6177496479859,
12.0650985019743,12.5124468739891,12.9594879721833,13.4065274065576,13.8530973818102,
14.2996471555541,14.7457263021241,15.1919151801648,15.6381626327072,16.0838732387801,
16.3617552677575,16.6396372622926),.UNSPECIFIED.);
#419=EDGE_CURVE('E206',#230,#337,#418,.T.);
#420=ORIENTED_EDGE('',*,*,#419,.F.);
#421=ORIENTED_EDGE('',*,*,#231,.F.);
#422=EDGE_LOOP('',(#330,#339,#420,#421));
#423=FACE_BOUND('',#422,.T.);
#424=ADVANCED_FACE('F162',(#423),#247,.T.);
#425=CARTESIAN_POINT('',(-34.9249999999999,0.,0.));
#426=DIRECTION('',(-1.,0.,0.));
#427=DIRECTION('',(0.,0.,1.));
#428=AXIS2_PLACEMENT_3D('',#425,#426,#427);
#429=CYLINDRICAL_SURFACE('',#428,46.9);
#430=DIRECTION('',(-1.,0.,0.));
#431=VECTOR('',#430,1.);
#432=CARTESIAN_POINT('',(-34.9249999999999,2.,46.857336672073));
#433=LINE('',#432,#431);
#434=CARTESIAN_POINT('',(-2.65,2.,46.857336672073));
#435=VERTEX_POINT('',#434);
#436=EDGE_CURVE('E153',#435,#328,#433,.T.);
#437=ORIENTED_EDGE('',*,*,#436,.F.);
#438=CARTESIAN_POINT('',(-2.65,0.,0.));
#439=DIRECTION('',(-1.,0.,0.));
#440=DIRECTION('',(0.,0.,1.));
#441=AXIS2_PLACEMENT_3D('',#438,#439,#440);
#442=CIRCLE('',#441,46.9);
#443=CARTESIAN_POINT('',(-2.65,-2.,46.857336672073));
#444=VERTEX_POINT('',#443);
#445=EDGE_CURVE('E127',#435,#444,#442,.T.);
#446=ORIENTED_EDGE('',*,*,#445,.T.);
#447=DIRECTION('',(-1.,0.,0.));
#448=VECTOR('',#447,1.);
#449=CARTESIAN_POINT('',(-34.9249999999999,-2.,46.857336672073));
#450=LINE('',#449,#448);
#451=EDGE_CURVE('E202',#337,#444,#450,.F.);
#452=ORIENTED_EDGE('',*,*,#451,.F.);
#453=ORIENTED_EDGE('',*,*,#338,.F.);
#454=EDGE_LOOP('',(#437,#446,#452,#453));
#455=FACE_BOUND('',#454,.T.);
#456=ADVANCED_FACE('F194',(#455),#429,.T.);
#457=CARTESIAN_POINT('',(-2.65,0.,0.));
#458=DIRECTION('',(-1.,0.,0.));
#459=DIRECTION('',(0.,0.,1.));
#460=AXIS2_PLACEMENT_3D('',#457,#458,#459);
#461=TOROIDAL_SURFACE('',#460,44.25,2.65);
#462=CARTESIAN_POINT('',(-1.96017625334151,2.,41.6433599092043));
#463=CARTESIAN_POINT('',(-1.81650131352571,2.,41.6821469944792));
#464=CARTESIAN_POINT('',(-1.67599906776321,2.,41.7331042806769));
#465=CARTESIAN_POINT('',(-1.40543215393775,2.,41.8579364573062));
#466=CARTESIAN_POINT('',(-1.27538034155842,2.,41.9318390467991));
#467=CARTESIAN_POINT('',(-1.02958607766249,2.,42.100396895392));
#468=CARTESIAN_POINT('',(-0.913836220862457,2.,42.1950413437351));
#469=CARTESIAN_POINT('',(-0.69988672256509,2.,42.4023806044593));
#470=CARTESIAN_POINT('',(-0.601682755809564,2.,42.5150709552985));
#471=CARTESIAN_POINT('',(-0.425478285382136,2.,42.7554243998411));
#472=CARTESIAN_POINT('',(-0.347495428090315,2.,42.8831004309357));
#473=CARTESIAN_POINT('',(-0.214043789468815,2.,43.1497275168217));
#474=CARTESIAN_POINT('',(-0.158576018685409,2.,43.2886790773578));
#475=CARTESIAN_POINT('',(-0.0716794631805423,2.,43.5740549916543));
#476=CARTESIAN_POINT('',(-0.0402742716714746,2.,43.7204865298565));
#477=CARTESIAN_POINT('',(-0.00247967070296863,2.,44.0165430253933));
#478=CARTESIAN_POINT('',(0.00390969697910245,2.,44.1661679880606));
#479=CARTESIAN_POINT('',(-0.00851218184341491,2.,44.4644440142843));
#480=CARTESIAN_POINT('',(-0.0273361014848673,2.,44.6130945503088));
#481=CARTESIAN_POINT('',(-0.0896771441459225,2.,44.9051242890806));
#482=CARTESIAN_POINT('',(-0.133194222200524,2.,45.0485035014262));
#483=CARTESIAN_POINT('',(-0.24368377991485,2.,45.3258920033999));
#484=CARTESIAN_POINT('',(-0.310652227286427,2.,45.4599028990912));
#485=CARTESIAN_POINT('',(-0.466152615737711,2.,45.7147687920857));
#486=CARTESIAN_POINT('',(-0.554684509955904,2.,45.8356238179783));
#487=CARTESIAN_POINT('',(-0.750732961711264,2.,46.0606528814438));
#488=CARTESIAN_POINT('',(-0.858235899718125,2.,46.1648387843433));
#489=CARTESIAN_POINT('',(-1.08922137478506,2.,46.3536632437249));
#490=CARTESIAN_POINT('',(-1.2127038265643,2.,46.4383019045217));
#491=CARTESIAN_POINT('',(-1.47202029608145,2.,46.5855466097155));
#492=CARTESIAN_POINT('',(-1.60784276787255,2.,46.6481729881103));
#493=CARTESIAN_POINT('',(-1.88807936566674,2.,46.749714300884));
#494=CARTESIAN_POINT('',(-2.03249345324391,2.,46.7886293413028));
#495=CARTESIAN_POINT('',(-2.32569533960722,2.,46.8416158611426));
#496=CARTESIAN_POINT('',(-2.47447971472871,2.,46.8557062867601));
#497=CARTESIAN_POINT('',(-2.77230141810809,2.,46.8586996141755));
#498=CARTESIAN_POINT('',(-2.92133874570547,2.,46.8476025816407));
#499=CARTESIAN_POINT('',(-3.21538639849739,2.,46.8005454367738));
#500=CARTESIAN_POINT('',(-3.36039798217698,2.,46.7645931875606));
#501=CARTESIAN_POINT('',(-3.64232922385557,2.,46.6688593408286));
#502=CARTESIAN_POINT('',(-3.77924887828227,2.,46.60907773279));
#503=CARTESIAN_POINT('',(-4.0411477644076,2.,46.467371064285));
#504=CARTESIAN_POINT('',(-4.16612407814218,2.,46.3854406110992));
#505=CARTESIAN_POINT('',(-4.40056048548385,2.,46.2017748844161));
#506=CARTESIAN_POINT('',(-4.51002053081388,2.,46.1000395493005));
#507=CARTESIAN_POINT('',(-4.71040294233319,2.,45.8795758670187));
#508=CARTESIAN_POINT('',(-4.80131197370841,2.,45.760835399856));
#509=CARTESIAN_POINT('',(-4.96192666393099,2.,45.5097890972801));
#510=CARTESIAN_POINT('',(-5.03163220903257,2.,45.3774831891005));
#511=CARTESIAN_POINT('',(-5.14792902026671,2.,45.1029306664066));
#512=CARTESIAN_POINT('',(-5.19449884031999,2.,44.9606749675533));
#513=CARTESIAN_POINT('',(-5.26311524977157,2.,44.6703674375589));
#514=CARTESIAN_POINT('',(-5.28516174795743,2.,44.5223155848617));
#515=CARTESIAN_POINT('',(-5.30411900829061,2.,44.2244971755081));
#516=CARTESIAN_POINT('',(-5.30101052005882,2.,44.0747293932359));
#517=CARTESIAN_POINT('',(-5.26970105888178,2.,43.7778394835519));
#518=CARTESIAN_POINT('',(-5.24149997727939,2.,43.6307173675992));
#519=CARTESIAN_POINT('',(-5.16079143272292,2.,43.3432568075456));
#520=CARTESIAN_POINT('',(-5.10827767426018,2.,43.202920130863));
#521=CARTESIAN_POINT('',(-4.9804255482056,2.,42.9330596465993));
#522=CARTESIAN_POINT('',(-4.90508716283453,2.,42.803535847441));
#523=CARTESIAN_POINT('',(-4.73375121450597,2.,42.5590365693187));
#524=CARTESIAN_POINT('',(-4.6377617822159,2.,42.4440553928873));
#525=CARTESIAN_POINT('',(-4.42782848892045,2.,42.231863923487));
#526=CARTESIAN_POINT('',(-4.31388541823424,2.,42.1346528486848));
#527=CARTESIAN_POINT('',(-4.07140555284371,2.,41.9608650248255));
#528=CARTESIAN_POINT('',(-3.94288431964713,2.,41.8842665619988));
#529=CARTESIAN_POINT('',(-3.67475938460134,2.,41.7537421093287));
#530=CARTESIAN_POINT('',(-3.53515299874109,2.,41.6998216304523));
#531=CARTESIAN_POINT('',(-3.24896069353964,2.,41.6162469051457));
#532=CARTESIAN_POINT('',(-3.10237895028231,2.,41.5865783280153));
#533=CARTESIAN_POINT('',(-2.80643630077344,2.,41.5523364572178));
#534=CARTESIAN_POINT('',(-2.65707897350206,2.,41.5477328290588));
#535=CARTESIAN_POINT('',(-2.41588761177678,2.,41.5606338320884));
#536=CARTESIAN_POINT('',(-2.32357629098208,2.,41.5704643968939));
#537=CARTESIAN_POINT('',(-2.14049130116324,2.,41.5997409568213));
#538=CARTESIAN_POINT('',(-2.04971763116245,2.,41.6191869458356));
#539=CARTESIAN_POINT('',(-1.96017625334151,2.,41.6433599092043));
#540=B_SPLINE_CURVE_WITH_KNOTS('',3,(#462,#463,#464,#465,#466,#467,#468,#469,#470,#471,#472,
#473,#474,#475,#476,#477,#478,#479,#480,#481,#482,#483,#484,#485,#486,#487,#488,#489,#490,#491,
#492,#493,#494,#495,#496,#497,#498,#499,#500,#501,#502,#503,#504,#505,#506,#507,#508,#509,#510,
#511,#512,#513,#514,#515,#516,#517,#518,#519,#520,#521,#522,#523,#524,#525,#526,#527,#528,#529,
#530,#531,#532,#533,#534,#535,#536,#537,#538,#539),.UNSPECIFIED.,.T.,.F.,(4,2,2,2,2,2,2,2,2,2,2,
2,2,2,2,2,2,2,2,2,2,2,2,2,2,2,2,2,2,2,2,2,2,2,2,2,2,2,4),(0.,0.446116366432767,
0.892773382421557,1.33919814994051,1.78551271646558,2.23221546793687,2.67893826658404,
3.12609851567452,3.57325951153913,4.02064535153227,4.46803037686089,4.91533851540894,
5.36264568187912,5.80963301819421,6.25661796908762,6.70318892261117,7.14975787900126,
7.59598586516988,8.04221268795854,8.4882984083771,8.93438432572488,9.3805789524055,
9.82677496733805,10.2732905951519,10.7198086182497,11.1667397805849,11.6136726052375,
12.0609474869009,12.5082243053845,12.9556170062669,13.4030100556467,13.8502272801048,
14.2974248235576,14.7441494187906,15.1909825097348,15.6375513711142,16.0835796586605,
16.3616093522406,16.6396388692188),.UNSPECIFIED.);
#541=CARTESIAN_POINT('',(0.,2.,44.2047791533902));
#542=VERTEX_POINT('',#541);
#543=EDGE_CURVE('E185',#542,#435,#540,.T.);
#544=ORIENTED_EDGE('',*,*,#543,.F.);
#545=CARTESIAN_POINT('',(0.,0.,0.));
#546=DIRECTION('',(-1.,0.,0.));
#547=DIRECTION('',(0.,0.,1.));
#548=AXIS2_PLACEMENT_3D('',#545,#546,#547);
#549=CIRCLE('',#548,44.25);
#550=CARTESIAN_POINT('',(0.,-2.,44.2047791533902));
#551=VERTEX_POINT('',#550);
#552=EDGE_CURVE('E125',#542,#551,#549,.T.);
#553=ORIENTED_EDGE('',*,*,#552,.T.);
#554=CARTESIAN_POINT('',(-1.96017625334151,-2.,41.6433599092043));
#555=CARTESIAN_POINT('',(-2.10373305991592,-2.,41.6046184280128));
#556=CARTESIAN_POINT('',(-2.25066537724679,-2.,41.577970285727));
#557=CARTESIAN_POINT('',(-2.54704041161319,-2.,41.5497033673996));
#558=CARTESIAN_POINT('',(-2.69648592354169,-2.,41.5481145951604));
#559=CARTESIAN_POINT('',(-2.99346341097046,-2.,41.5700573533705));
#560=CARTESIAN_POINT('',(-3.14099626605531,-2.,41.5935768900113));
#561=CARTESIAN_POINT('',(-3.42997930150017,-2.,41.6650428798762));
#562=CARTESIAN_POINT('',(-3.57143096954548,-2.,41.7129833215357));
#563=CARTESIAN_POINT('',(-3.84431813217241,-2.,41.8319313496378));
#564=CARTESIAN_POINT('',(-3.97575126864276,-2.,41.9029443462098));
#565=CARTESIAN_POINT('',(-4.22484800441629,-2.,42.0660135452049));
#566=CARTESIAN_POINT('',(-4.34251101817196,-2.,42.1580706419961));
#567=CARTESIAN_POINT('',(-4.56082672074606,-2.,42.3606904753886));
#568=CARTESIAN_POINT('',(-4.66146549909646,-2.,42.4712681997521));
#569=CARTESIAN_POINT('',(-4.84277444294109,-2.,42.7077338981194));
#570=CARTESIAN_POINT('',(-4.9234445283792,-2.,42.8336219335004));
#571=CARTESIAN_POINT('',(-5.06261852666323,-2.,43.0972825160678));
#572=CARTESIAN_POINT('',(-5.12109814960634,-2.,43.2350678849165));
#573=CARTESIAN_POINT('',(-5.2141168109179,-2.,43.5184955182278));
#574=CARTESIAN_POINT('',(-5.24865577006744,-2.,43.664137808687));
#575=CARTESIAN_POINT('',(-5.29283710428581,-2.,43.9592740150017));
#576=CARTESIAN_POINT('',(-5.30245894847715,-2.,44.1087710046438));
#577=CARTESIAN_POINT('',(-5.29647366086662,-2.,44.4072595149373));
#578=CARTESIAN_POINT('',(-5.28086644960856,-2.,44.5562510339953));
#579=CARTESIAN_POINT('',(-5.22485574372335,-2.,44.8495308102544));
#580=CARTESIAN_POINT('',(-5.18444705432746,-2.,44.9938180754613));
#581=CARTESIAN_POINT('',(-5.07996898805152,-2.,45.2735559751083));
#582=CARTESIAN_POINT('',(-5.01589965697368,-2.,45.4090066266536));
#583=CARTESIAN_POINT('',(-4.86594509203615,-2.,45.6671600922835));
#584=CARTESIAN_POINT('',(-4.78006946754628,-2.,45.7898684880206));
#585=CARTESIAN_POINT('',(-4.58891975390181,-2.,46.019110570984));
#586=CARTESIAN_POINT('',(-4.48364574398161,-2.,46.1256443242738));
#587=CARTESIAN_POINT('',(-4.25678310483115,-2.,46.3194149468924));
#588=CARTESIAN_POINT('',(-4.13520848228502,-2.,46.406668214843));
#589=CARTESIAN_POINT('',(-3.8791255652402,-2.,46.5595040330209));
#590=CARTESIAN_POINT('',(-3.74461733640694,-2.,46.6250866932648));
#591=CARTESIAN_POINT('',(-3.46661554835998,-2.,46.7326592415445));
#592=CARTESIAN_POINT('',(-3.32313017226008,-2.,46.7746702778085));
#593=CARTESIAN_POINT('',(-3.03114114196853,-2.,46.8339908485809));
#594=CARTESIAN_POINT('',(-2.88263750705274,-2.,46.8513004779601));
#595=CARTESIAN_POINT('',(-2.58492186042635,-2.,46.8607210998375));
#596=CARTESIAN_POINT('',(-2.43571032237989,-2.,46.8528470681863));
#597=CARTESIAN_POINT('',(-2.14072781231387,-2.,46.8121580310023));
#598=CARTESIAN_POINT('',(-1.99495683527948,-2.,46.7793430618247));
#599=CARTESIAN_POINT('',(-1.71100309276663,-2.,46.6897117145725));
#600=CARTESIAN_POINT('',(-1.57281976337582,-2.,46.6328971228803));
#601=CARTESIAN_POINT('',(-1.3079465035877,-2.,46.4968858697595));
#602=CARTESIAN_POINT('',(-1.18125659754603,-2.,46.4176891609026));
#603=CARTESIAN_POINT('',(-0.942900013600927,-2.,46.2391251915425));
#604=CARTESIAN_POINT('',(-0.831240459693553,-2.,46.1397484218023));
#605=CARTESIAN_POINT('',(-0.626172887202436,-2.,45.9236737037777));
#606=CARTESIAN_POINT('',(-0.532764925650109,-2.,45.8069757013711));
#607=CARTESIAN_POINT('',(-0.366766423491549,-2.,45.5594660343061));
#608=CARTESIAN_POINT('',(-0.294193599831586,-2.,45.4286424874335));
#609=CARTESIAN_POINT('',(-0.172018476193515,-2.,45.1566761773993));
#610=CARTESIAN_POINT('',(-0.122416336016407,-2.,45.015533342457));
#611=CARTESIAN_POINT('',(-0.0475457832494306,-2.,44.7267988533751));
#612=CARTESIAN_POINT('',(-0.0222993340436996,-2.,44.5792015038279));
#613=CARTESIAN_POINT('',(0.00307169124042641,-2.,44.2818627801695));
#614=CARTESIAN_POINT('',(0.00319611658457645,-2.,44.1321213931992));
#615=CARTESIAN_POINT('',(-0.0216865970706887,-2.,43.8346505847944));
#616=CARTESIAN_POINT('',(-0.046708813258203,-2.,43.6869224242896));
#617=CARTESIAN_POINT('',(-0.121199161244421,-2.,43.3977692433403));
#618=CARTESIAN_POINT('',(-0.170666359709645,-2.,43.2563439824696));
#619=CARTESIAN_POINT('',(-0.292639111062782,-2.,42.9838269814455));
#620=CARTESIAN_POINT('',(-0.365141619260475,-2.,42.8527338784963));
#621=CARTESIAN_POINT('',(-0.531162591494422,-2.,42.6045571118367));
#622=CARTESIAN_POINT('',(-0.624686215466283,-2.,42.4874768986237));
#623=CARTESIAN_POINT('',(-0.830049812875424,-2.,42.2707321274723));
#624=CARTESIAN_POINT('',(-0.941886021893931,-2.,42.1710639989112));
#625=CARTESIAN_POINT('',(-1.18063794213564,-2.,41.9920442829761));
#626=CARTESIAN_POINT('',(-1.30753524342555,-2.,41.9126682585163));
#627=CARTESIAN_POINT('',(-1.52294179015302,-2.,41.8019884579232));
#628=CARTESIAN_POINT('',(-1.60799857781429,-2.,41.7638204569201));
#629=CARTESIAN_POINT('',(-1.78165417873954,-2.,41.6966399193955));
#630=CARTESIAN_POINT('',(-1.87025299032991,-2.,41.6676273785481));
#631=CARTESIAN_POINT('',(-1.96017625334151,-2.,41.6433599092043));
#632=B_SPLINE_CURVE_WITH_KNOTS('',3,(#554,#555,#556,#557,#558,#559,#560,#561,#562,#563,#564,
#565,#566,#567,#568,#569,#570,#571,#572,#573,#574,#575,#576,#577,#578,#579,#580,#581,#582,#583,
#584,#585,#586,#587,#588,#589,#590,#591,#592,#593,#594,#595,#596,#597,#598,#599,#600,#601,#602,
#603,#604,#605,#606,#607,#608,#609,#610,#611,#612,#613,#614,#615,#616,#617,#618,#619,#620,#621,
#622,#623,#624,#625,#626,#627,#628,#629,#630,#631),.UNSPECIFIED.,.T.,.F.,(4,2,2,2,2,2,2,2,2,2,2,
2,2,2,2,2,2,2,2,2,2,2,2,2,2,2,2,2,2,2,2,2,2,2,2,2,2,2,4),(0.,0.445737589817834,
0.892008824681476,1.33806697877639,1.78401538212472,2.23006842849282,2.67614043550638,
3.12257518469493,3.5690117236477,4.01593553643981,4.46286082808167,4.91015425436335,
5.35744908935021,5.8048376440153,6.25222533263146,6.69941621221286,7.14660526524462,
7.593412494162,8.04021745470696,8.48662090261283,8.93302263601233,9.37915895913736,
9.82529463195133,10.2713971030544,10.7175005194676,11.163814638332,11.6101301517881,
12.0568240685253,12.5035210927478,12.9506205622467,13.3977227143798,13.8450930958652,
14.2924463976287,14.7397405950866,15.1871447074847,15.6344569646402,16.0812279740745,
16.3604358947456,16.6396436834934),.UNSPECIFIED.);
#633=EDGE_CURVE('E104',#444,#551,#632,.T.);
#634=ORIENTED_EDGE('',*,*,#633,.F.);
#635=ORIENTED_EDGE('',*,*,#445,.F.);
#636=EDGE_LOOP('',(#544,#553,#634,#635));
#637=FACE_BOUND('',#636,.T.);
#638=ADVANCED_FACE('F190',(#637),#461,.T.);
#639=CARTESIAN_POINT('',(0.,35.8,0.));
#640=DIRECTION('',(-1.,0.,0.));
#641=DIRECTION('',(0.,0.,1.));
#642=AXIS2_PLACEMENT_3D('',#639,#640,#641);
#643=PLANE('',#642);
#644=DIRECTION('',(0.,0.,-1.));
#645=VECTOR('',#644,1.);
#646=CARTESIAN_POINT('',(0.,2.,47.838));
#647=LINE('',#646,#645);
#648=CARTESIAN_POINT('',(0.,2.,35.7440904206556));
#649=VERTEX_POINT('',#648);
#650=EDGE_CURVE('E110',#542,#649,#647,.T.);
#651=ORIENTED_EDGE('',*,*,#650,.T.);
#652=CARTESIAN_POINT('',(0.,0.,0.));
#653=DIRECTION('',(-1.,0.,0.));
#654=DIRECTION('',(0.,0.,1.));
#655=AXIS2_PLACEMENT_3D('',#652,#653,#654);
#656=CIRCLE('',#655,35.8);
#657=CARTESIAN_POINT('',(0.,-2.,35.7440904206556));
#658=VERTEX_POINT('',#657);
#659=EDGE_CURVE('E117',#649,#658,#656,.T.);
#660=ORIENTED_EDGE('',*,*,#659,.T.);
#661=DIRECTION('',(0.,0.,1.));
#662=VECTOR('',#661,1.);
#663=CARTESIAN_POINT('',(0.,-2.,0.));
#664=LINE('',#663,#662);
#665=EDGE_CURVE('E101',#658,#551,#664,.T.);
#666=ORIENTED_EDGE('',*,*,#665,.T.);
#667=ORIENTED_EDGE('',*,*,#552,.F.);
#668=EDGE_LOOP('',(#651,#660,#666,#667));
#669=FACE_BOUND('',#668,.T.);
#670=ADVANCED_FACE('F124',(#669),#643,.F.);
#671=CARTESIAN_POINT('',(-2.65,0.,0.));
#672=DIRECTION('',(-1.,0.,0.));
#673=DIRECTION('',(0.,0.,1.));
#674=AXIS2_PLACEMENT_3D('',#671,#672,#673);
#675=TOROIDAL_SURFACE('',#674,35.8,2.65);
#676=ORIENTED_EDGE('',*,*,#659,.F.);
#677=CARTESIAN_POINT('',(-1.66227605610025,2.,33.2809148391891));
#678=CARTESIAN_POINT('',(-1.80014880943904,2.,33.2254427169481));
#679=CARTESIAN_POINT('',(-1.94280322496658,2.,33.1815670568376));
#680=CARTESIAN_POINT('',(-2.23357176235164,2.,33.1183549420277));
#681=CARTESIAN_POINT('',(-2.38169217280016,2.,33.0990477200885));
#682=CARTESIAN_POINT('',(-2.67901719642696,2.,33.0855931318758));
#683=CARTESIAN_POINT('',(-2.8282212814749,2.,33.0914342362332));
#684=CARTESIAN_POINT('',(-3.12348917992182,2.,33.1280866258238));
#685=CARTESIAN_POINT('',(-3.26955375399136,2.,33.1588917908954));
#686=CARTESIAN_POINT('',(-3.55443956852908,2.,33.244577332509));
#687=CARTESIAN_POINT('',(-3.69326091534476,2.,33.2994573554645));
#688=CARTESIAN_POINT('',(-3.95973762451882,2.,33.431724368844));
#689=CARTESIAN_POINT('',(-4.08739251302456,2.,33.5091123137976));
#690=CARTESIAN_POINT('',(-4.32804521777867,2.,33.6842713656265));
#691=CARTESIAN_POINT('',(-4.44102861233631,2.,33.7820622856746));
#692=CARTESIAN_POINT('',(-4.64900784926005,2.,33.9951957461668));
#693=CARTESIAN_POINT('',(-4.74400356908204,2.,34.1105384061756));
#694=CARTESIAN_POINT('',(-4.91347995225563,2.,34.3557072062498));
#695=CARTESIAN_POINT('',(-4.98792610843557,2.,34.4855571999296));
#696=CARTESIAN_POINT('',(-5.1139995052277,2.,34.7558984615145));
#697=CARTESIAN_POINT('',(-5.16562658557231,2.,34.8963898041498));
#698=CARTESIAN_POINT('',(-5.24467094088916,2.,35.1842519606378));
#699=CARTESIAN_POINT('',(-5.27205192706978,2.,35.331632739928));
#700=CARTESIAN_POINT('',(-5.30170028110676,2.,35.6288995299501));
#701=CARTESIAN_POINT('',(-5.30396749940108,2.,35.7787855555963));
#702=CARTESIAN_POINT('',(-5.28331455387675,2.,36.0769111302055));
#703=CARTESIAN_POINT('',(-5.26037796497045,2.,36.2251495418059));
#704=CARTESIAN_POINT('',(-5.18993387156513,2.,36.5156689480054));
#705=CARTESIAN_POINT('',(-5.14242639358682,2.,36.6579499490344));
#706=CARTESIAN_POINT('',(-5.02420075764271,2.,36.9324535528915));
#707=CARTESIAN_POINT('',(-4.95349152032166,2.,37.0646799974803));
#708=CARTESIAN_POINT('',(-4.79085328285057,2.,37.3153666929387));
#709=CARTESIAN_POINT('',(-4.69892439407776,2.,37.4338270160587));
#710=CARTESIAN_POINT('',(-4.49656728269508,2.,37.6534704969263));
#711=CARTESIAN_POINT('',(-4.38616050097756,2.,37.7546734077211));
#712=CARTESIAN_POINT('',(-4.14990301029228,2.,37.9370758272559));
#713=CARTESIAN_POINT('',(-4.02405241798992,2.,38.0182754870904));
#714=CARTESIAN_POINT('',(-3.76066836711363,2.,38.1582477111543));
#715=CARTESIAN_POINT('',(-3.62315143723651,2.,38.2170513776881));
#716=CARTESIAN_POINT('',(-3.34019028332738,2.,38.3107082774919));
#717=CARTESIAN_POINT('',(-3.19474611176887,2.,38.3455616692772));
#718=CARTESIAN_POINT('',(-2.90022938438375,2.,38.3902948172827));
#719=CARTESIAN_POINT('',(-2.75116095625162,2.,38.4002017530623));
#720=CARTESIAN_POINT('',(-2.45347813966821,2.,38.3948374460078));
#721=CARTESIAN_POINT('',(-2.30486374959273,2.,38.3795662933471));
#722=CARTESIAN_POINT('',(-2.01236926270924,2.,38.3242941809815));
#723=CARTESIAN_POINT('',(-1.86848729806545,2.,38.284303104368));
#724=CARTESIAN_POINT('',(-1.58947527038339,2.,38.1807427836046));
#725=CARTESIAN_POINT('',(-1.45434521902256,2.,38.1171735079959));
#726=CARTESIAN_POINT('',(-1.19660764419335,2.,37.9682386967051));
#727=CARTESIAN_POINT('',(-1.07400547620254,2.,37.8828638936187));
#728=CARTESIAN_POINT('',(-0.84485457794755,2.,37.6927640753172));
#729=CARTESIAN_POINT('',(-0.738305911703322,2.,37.5880389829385));
#730=CARTESIAN_POINT('',(-0.544157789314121,2.,37.3620899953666));
#731=CARTESIAN_POINT('',(-0.456579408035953,2.,37.2408479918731));
#732=CARTESIAN_POINT('',(-0.302987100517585,2.,36.9853981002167));
#733=CARTESIAN_POINT('',(-0.236973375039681,2.,36.8511900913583));
#734=CARTESIAN_POINT('',(-0.128288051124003,2.,36.573418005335));
#735=CARTESIAN_POINT('',(-0.0856490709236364,2.,36.4298411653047));
#736=CARTESIAN_POINT('',(-0.0250501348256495,2.,36.1375701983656));
#737=CARTESIAN_POINT('',(-0.00709040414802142,2.,35.9888760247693));
#738=CARTESIAN_POINT('',(0.00365468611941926,2.,35.6904082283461));
#739=CARTESIAN_POINT('',(-0.00358908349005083,2.,35.5406335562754));
#740=CARTESIAN_POINT('',(-0.0431087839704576,2.,35.2444292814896));
#741=CARTESIAN_POINT('',(-0.0753838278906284,2.,35.0979995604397));
#742=CARTESIAN_POINT('',(-0.164065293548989,2.,34.8125986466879));
#743=CARTESIAN_POINT('',(-0.22047786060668,2.,34.6736293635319));
#744=CARTESIAN_POINT('',(-0.355866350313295,2.,34.4071061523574));
#745=CARTESIAN_POINT('',(-0.434847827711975,2.,34.2795550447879));
#746=CARTESIAN_POINT('',(-0.613101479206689,2.,34.0395789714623));
#747=CARTESIAN_POINT('',(-0.712369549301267,2.,33.9271509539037));
#748=CARTESIAN_POINT('',(-0.928328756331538,2.,33.7206985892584));
#749=CARTESIAN_POINT('',(-1.04499863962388,2.,33.6266521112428));
#750=CARTESIAN_POINT('',(-1.24601499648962,2.,33.4908790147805));
#751=CARTESIAN_POINT('',(-1.32611370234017,2.,33.442745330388));
#752=CARTESIAN_POINT('',(-1.49093794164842,2.,33.3551872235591));
#753=CARTESIAN_POINT('',(-1.5756634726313,2.,33.3157627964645));
#754=CARTESIAN_POINT('',(-1.66227605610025,2.,33.2809148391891));
#755=B_SPLINE_CURVE_WITH_KNOTS('',3,(#677,#678,#679,#680,#681,#682,#683,#684,#685,#686,#687,
#688,#689,#690,#691,#692,#693,#694,#695,#696,#697,#698,#699,#700,#701,#702,#703,#704,#705,#706,
#707,#708,#709,#710,#711,#712,#713,#714,#715,#716,#717,#718,#719,#720,#721,#722,#723,#724,#725,
#726,#727,#728,#729,#730,#731,#732,#733,#734,#735,#736,#737,#738,#739,#740,#741,#742,#743,#744,
#745,#746,#747,#748,#749,#750,#751,#752,#753,#754),.UNSPECIFIED.,.T.,.F.,(4,2,2,2,2,2,2,2,2,2,2,
2,2,2,2,2,2,2,2,2,2,2,2,2,2,2,2,2,2,2,2,2,2,2,2,2,2,2,4),(0.,0.445500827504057,
0.891531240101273,1.33735718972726,1.7830738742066,2.22878401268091,2.67451305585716,
3.12067697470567,3.56684393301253,4.01375560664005,4.46067041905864,4.9082529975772,
5.35583824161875,5.80371534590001,6.25159196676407,6.6992965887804,7.1469988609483,
7.59418519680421,8.04136815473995,8.48792780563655,8.93448450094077,9.38055445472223,
9.8266228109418,10.2725129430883,10.7184036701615,11.1644842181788,11.6105665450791,
12.0571419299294,12.5037214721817,12.9509226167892,13.3981278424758,13.8458501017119,
14.2935564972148,14.7413769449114,15.1893077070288,15.6371479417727,16.0844456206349,
16.3643123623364,16.6441789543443),.UNSPECIFIED.);
#756=CARTESIAN_POINT('',(-2.65,2.,33.0896131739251));
#757=VERTEX_POINT('',#756);
#758=EDGE_CURVE('E175',#649,#757,#755,.T.);
#759=ORIENTED_EDGE('',*,*,#758,.T.);
#760=CARTESIAN_POINT('',(-2.65,0.,0.));
#761=DIRECTION('',(-1.,0.,0.));
#762=DIRECTION('',(0.,0.,1.));
#763=AXIS2_PLACEMENT_3D('',#760,#761,#762);
#764=CIRCLE('',#763,33.15);
#765=CARTESIAN_POINT('',(-2.65,-2.,33.0896131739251));
#766=VERTEX_POINT('',#765);
#767=EDGE_CURVE('E119',#757,#766,#764,.T.);
#768=ORIENTED_EDGE('',*,*,#767,.T.);
#769=CARTESIAN_POINT('',(-1.66227605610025,-2.,33.2809148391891));
#770=CARTESIAN_POINT('',(-1.52415640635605,-2.,33.3365005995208));
#771=CARTESIAN_POINT('',(-1.39063534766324,-2.,33.4038061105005));
#772=CARTESIAN_POINT('',(-1.13668576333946,-2.,33.559947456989));
#773=CARTESIAN_POINT('',(-1.01627341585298,-2.,33.6488094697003));
#774=CARTESIAN_POINT('',(-0.792128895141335,-2.,33.8454427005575));
#775=CARTESIAN_POINT('',(-0.688387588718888,-2.,33.9532034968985));
#776=CARTESIAN_POINT('',(-0.500471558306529,-2.,34.1845636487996));
#777=CARTESIAN_POINT('',(-0.416292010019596,-2.,34.3081590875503));
#778=CARTESIAN_POINT('',(-0.269727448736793,-2.,34.5678800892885));
#779=CARTESIAN_POINT('',(-0.20737191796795,-2.,34.7040222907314));
#780=CARTESIAN_POINT('',(-0.106365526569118,-2.,34.9848391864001));
#781=CARTESIAN_POINT('',(-0.0677157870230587,-2.,35.1295142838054));
#782=CARTESIAN_POINT('',(-0.01517727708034,-2.,35.4234869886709));
#783=CARTESIAN_POINT('',(-0.00132068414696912,-2.,35.5727903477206));
#784=CARTESIAN_POINT('',(0.00114038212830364,-2.,35.8716051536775));
#785=CARTESIAN_POINT('',(-0.0102551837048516,-2.,36.0211166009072));
#786=CARTESIAN_POINT('',(-0.0579899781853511,-2.,36.3161608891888));
#787=CARTESIAN_POINT('',(-0.094338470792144,-2.,36.4616922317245));
#788=CARTESIAN_POINT('',(-0.190967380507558,-2.,36.7445804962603));
#789=CARTESIAN_POINT('',(-0.251247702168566,-2.,36.88193745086));
#790=CARTESIAN_POINT('',(-0.393994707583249,-2.,37.1444813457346));
#791=CARTESIAN_POINT('',(-0.476447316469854,-2.,37.2696759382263));
#792=CARTESIAN_POINT('',(-0.661225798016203,-2.,37.5044228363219));
#793=CARTESIAN_POINT('',(-0.763551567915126,-2.,37.6139752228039));
#794=CARTESIAN_POINT('',(-0.985033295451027,-2.,37.8141771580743));
#795=CARTESIAN_POINT('',(-1.10416763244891,-2.,37.9048506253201));
#796=CARTESIAN_POINT('',(-1.35598520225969,-2.,38.0648772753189));
#797=CARTESIAN_POINT('',(-1.48866832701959,-2.,38.1342306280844));
#798=CARTESIAN_POINT('',(-1.76362266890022,-2.,38.24955112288));
#799=CARTESIAN_POINT('',(-1.90588058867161,-2.,38.2955499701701));
#800=CARTESIAN_POINT('',(-2.19610337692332,-2.,38.3629866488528));
#801=CARTESIAN_POINT('',(-2.34406821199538,-2.,38.3844246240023));
#802=CARTESIAN_POINT('',(-2.64135700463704,-2.,38.4021172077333));
#803=CARTESIAN_POINT('',(-2.79067956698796,-2.,38.3983952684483));
#804=CARTESIAN_POINT('',(-3.08657903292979,-2.,38.3659299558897));
#805=CARTESIAN_POINT('',(-3.23315594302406,-2.,38.3371866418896));
#806=CARTESIAN_POINT('',(-3.51937798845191,-2.,38.2555080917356));
#807=CARTESIAN_POINT('',(-3.65902435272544,-2.,38.2025771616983));
#808=CARTESIAN_POINT('',(-3.92745654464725,-2.,38.074036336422));
#809=CARTESIAN_POINT('',(-4.0562423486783,-2.,37.998426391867));
#810=CARTESIAN_POINT('',(-4.29938894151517,-2.,37.8266278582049));
#811=CARTESIAN_POINT('',(-4.41374051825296,-2.,37.7304262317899));
#812=CARTESIAN_POINT('',(-4.62469425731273,-2.,37.5202117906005));
#813=CARTESIAN_POINT('',(-4.72129631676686,-2.,37.4061988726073));
#814=CARTESIAN_POINT('',(-4.89413772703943,-2.,37.1634496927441));
#815=CARTESIAN_POINT('',(-4.97035186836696,-2.,37.0346954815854));
#816=CARTESIAN_POINT('',(-5.10011688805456,-2.,36.7662326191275));
#817=CARTESIAN_POINT('',(-5.15366758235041,-2.,36.6265238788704));
#818=CARTESIAN_POINT('',(-5.23666124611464,-2.,36.3399109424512));
#819=CARTESIAN_POINT('',(-5.26607081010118,-2.,36.1929970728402));
#820=CARTESIAN_POINT('',(-5.29983426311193,-2.,35.8963178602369));
#821=CARTESIAN_POINT('',(-5.30418801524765,-2.,35.7465525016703));
#822=CARTESIAN_POINT('',(-5.28771228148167,-2.,35.4482668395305));
#823=CARTESIAN_POINT('',(-5.2668583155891,-2.,35.2997478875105));
#824=CARTESIAN_POINT('',(-5.20051494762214,-2.,35.0083173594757));
#825=CARTESIAN_POINT('',(-5.15502544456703,-2.,34.8654058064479));
#826=CARTESIAN_POINT('',(-5.04068825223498,-2.,34.5892386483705));
#827=CARTESIAN_POINT('',(-4.97183856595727,-2.,34.4559838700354));
#828=CARTESIAN_POINT('',(-4.81272454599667,-2.,34.2029386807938));
#829=CARTESIAN_POINT('',(-4.72246025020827,-2.,34.0831482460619));
#830=CARTESIAN_POINT('',(-4.52316315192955,-2.,33.8605573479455));
#831=CARTESIAN_POINT('',(-4.41414785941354,-2.,33.7577412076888));
#832=CARTESIAN_POINT('',(-4.18038271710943,-2.,33.5719106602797));
#833=CARTESIAN_POINT('',(-4.05563362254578,-2.,33.4888953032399));
#834=CARTESIAN_POINT('',(-3.79417145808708,-2.,33.3451702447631));
#835=CARTESIAN_POINT('',(-3.65747957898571,-2.,33.2844219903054));
#836=CARTESIAN_POINT('',(-3.37578848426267,-2.,33.1867630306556));
#837=CARTESIAN_POINT('',(-3.2307872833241,-2.,33.1498580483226));
#838=CARTESIAN_POINT('',(-2.93681529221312,-2.,33.1009935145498));
#839=CARTESIAN_POINT('',(-2.78784892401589,-2.,33.0890072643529));
#840=CARTESIAN_POINT('',(-2.49014667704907,-2.,33.0902648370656));
#841=CARTESIAN_POINT('',(-2.34141073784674,-2.,33.1034780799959));
#842=CARTESIAN_POINT('',(-2.10380886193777,-2.,33.1449585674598));
#843=CARTESIAN_POINT('',(-2.01355273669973,-2.,33.1656528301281));
#844=CARTESIAN_POINT('',(-1.83569792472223,-2.,33.2163613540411));
#845=CARTESIAN_POINT('',(-1.7480992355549,-2.,33.2463756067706));
#846=CARTESIAN_POINT('',(-1.66227605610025,-2.,33.2809148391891));
#847=B_SPLINE_CURVE_WITH_KNOTS('',3,(#769,#770,#771,#772,#773,#774,#775,#776,#777,#778,#779,
#780,#781,#782,#783,#784,#785,#786,#787,#788,#789,#790,#791,#792,#793,#794,#795,#796,#797,#798,
#799,#800,#801,#802,#803,#804,#805,#806,#807,#808,#809,#810,#811,#812,#813,#814,#815,#816,#817,
#818,#819,#820,#821,#822,#823,#824,#825,#826,#827,#828,#829,#830,#831,#832,#833,#834,#835,#836,
#837,#838,#839,#840,#841,#842,#843,#844,#845,#846),.UNSPECIFIED.,.T.,.F.,(4,2,2,2,2,2,2,2,2,2,2,
2,2,2,2,2,2,2,2,2,2,2,2,2,2,2,2,2,2,2,2,2,2,2,2,2,2,2,4),(0.,0.446317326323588,
0.893179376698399,1.33979577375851,1.78630190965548,2.23340892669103,2.68053708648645,
3.12824512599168,3.57595386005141,4.02382889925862,4.47170215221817,4.9192917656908,
5.36687906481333,5.81389579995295,6.26090897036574,6.7073136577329,7.1537157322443,
7.59970176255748,8.04568673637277,8.4915923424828,8.93749891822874,9.38368865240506,
9.8298809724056,10.2766224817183,10.7233676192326,11.170729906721,11.6180946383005,
12.0658941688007,12.5136955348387,12.9615351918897,13.409374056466,13.856796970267,
14.3041984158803,14.7508215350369,15.1975518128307,15.6438032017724,16.0895134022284,
16.3668411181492,16.6441685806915),.UNSPECIFIED.);
#848=EDGE_CURVE('E61',#766,#658,#847,.T.);
#849=ORIENTED_EDGE('',*,*,#848,.T.);
#850=EDGE_LOOP('',(#676,#759,#768,#849));
#851=FACE_BOUND('',#850,.T.);
#852=ADVANCED_FACE('F115',(#851),#675,.T.);
#853=CARTESIAN_POINT('',(-34.9249999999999,0.,0.));
#854=DIRECTION('',(-1.,0.,0.));
#855=DIRECTION('',(0.,0.,1.));
#856=AXIS2_PLACEMENT_3D('',#853,#854,#855);
#857=CYLINDRICAL_SURFACE('',#856,33.15);
#858=DIRECTION('',(-1.,0.,0.));
#859=VECTOR('',#858,1.);
#860=CARTESIAN_POINT('',(-34.9249999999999,2.,33.0896131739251));
#861=LINE('',#860,#859);
#862=EDGE_CURVE('E11',#30,#757,#861,.F.);
#863=ORIENTED_EDGE('',*,*,#862,.F.);
#864=ORIENTED_EDGE('',*,*,#33,.T.);
#865=DIRECTION('',(-1.,0.,0.));
#866=VECTOR('',#865,1.);
#867=CARTESIAN_POINT('',(-34.9249999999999,-2.,33.0896131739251));
#868=LINE('',#867,#866);
#869=EDGE_CURVE('E47',#766,#32,#868,.T.);
#870=ORIENTED_EDGE('',*,*,#869,.F.);
#871=ORIENTED_EDGE('',*,*,#767,.F.);
#872=EDGE_LOOP('',(#863,#864,#870,#871));
#873=FACE_BOUND('',#872,.T.);
#874=ADVANCED_FACE('F151',(#873),#857,.F.);
#875=CARTESIAN_POINT('',(-8.,-2.,0.));
#876=DIRECTION('',(0.,1.,0.));
#877=DIRECTION('',(0.,0.,1.));
#878=AXIS2_PLACEMENT_3D('',#875,#876,#877);
#879=PLANE('',#878);
#880=ORIENTED_EDGE('',*,*,#419,.T.);
#881=ORIENTED_EDGE('',*,*,#451,.T.);
#882=ORIENTED_EDGE('',*,*,#633,.T.);
#883=ORIENTED_EDGE('',*,*,#665,.F.);
#884=ORIENTED_EDGE('',*,*,#848,.F.);
#885=ORIENTED_EDGE('',*,*,#869,.T.);
#886=ORIENTED_EDGE('',*,*,#206,.F.);
#887=ORIENTED_EDGE('',*,*,#237,.T.);
#888=EDGE_LOOP('',(#880,#881,#882,#883,#884,#885,#886,#887));
#889=FACE_BOUND('',#888,.T.);
#890=ADVANCED_FACE('F102',(#889),#879,.T.);
#891=CARTESIAN_POINT('',(-8.,2.,47.838));
#892=DIRECTION('',(0.,-1.,0.));
#893=DIRECTION('',(0.,0.,-1.));
#894=AXIS2_PLACEMENT_3D('',#891,#892,#893);
#895=PLANE('',#894);
#896=ORIENTED_EDGE('',*,*,#329,.T.);
#897=ORIENTED_EDGE('',*,*,#222,.T.);
#898=ORIENTED_EDGE('',*,*,#116,.F.);
#899=ORIENTED_EDGE('',*,*,#862,.T.);
#900=ORIENTED_EDGE('',*,*,#758,.F.);
#901=ORIENTED_EDGE('',*,*,#650,.F.);
#902=ORIENTED_EDGE('',*,*,#543,.T.);
#903=ORIENTED_EDGE('',*,*,#436,.T.);
#904=EDGE_LOOP('',(#896,#897,#898,#899,#900,#901,#902,#903));
#905=FACE_BOUND('',#904,.T.);
#906=ADVANCED_FACE('F165',(#905),#895,.T.);
#907=CLOSED_SHELL('',(#210,#242,#424,#456,#638,#670,#852,#874,#890,#906));
#908=MANIFOLD_SOLID_BREP('B2',#907);
#909=ADVANCED_BREP_SHAPE_REPRESENTATION('',(#18,#908),#14);
#910=SHAPE_DEFINITION_REPRESENTATION(#9,#909);
ENDSEC;
END-ISO-10303-21;
